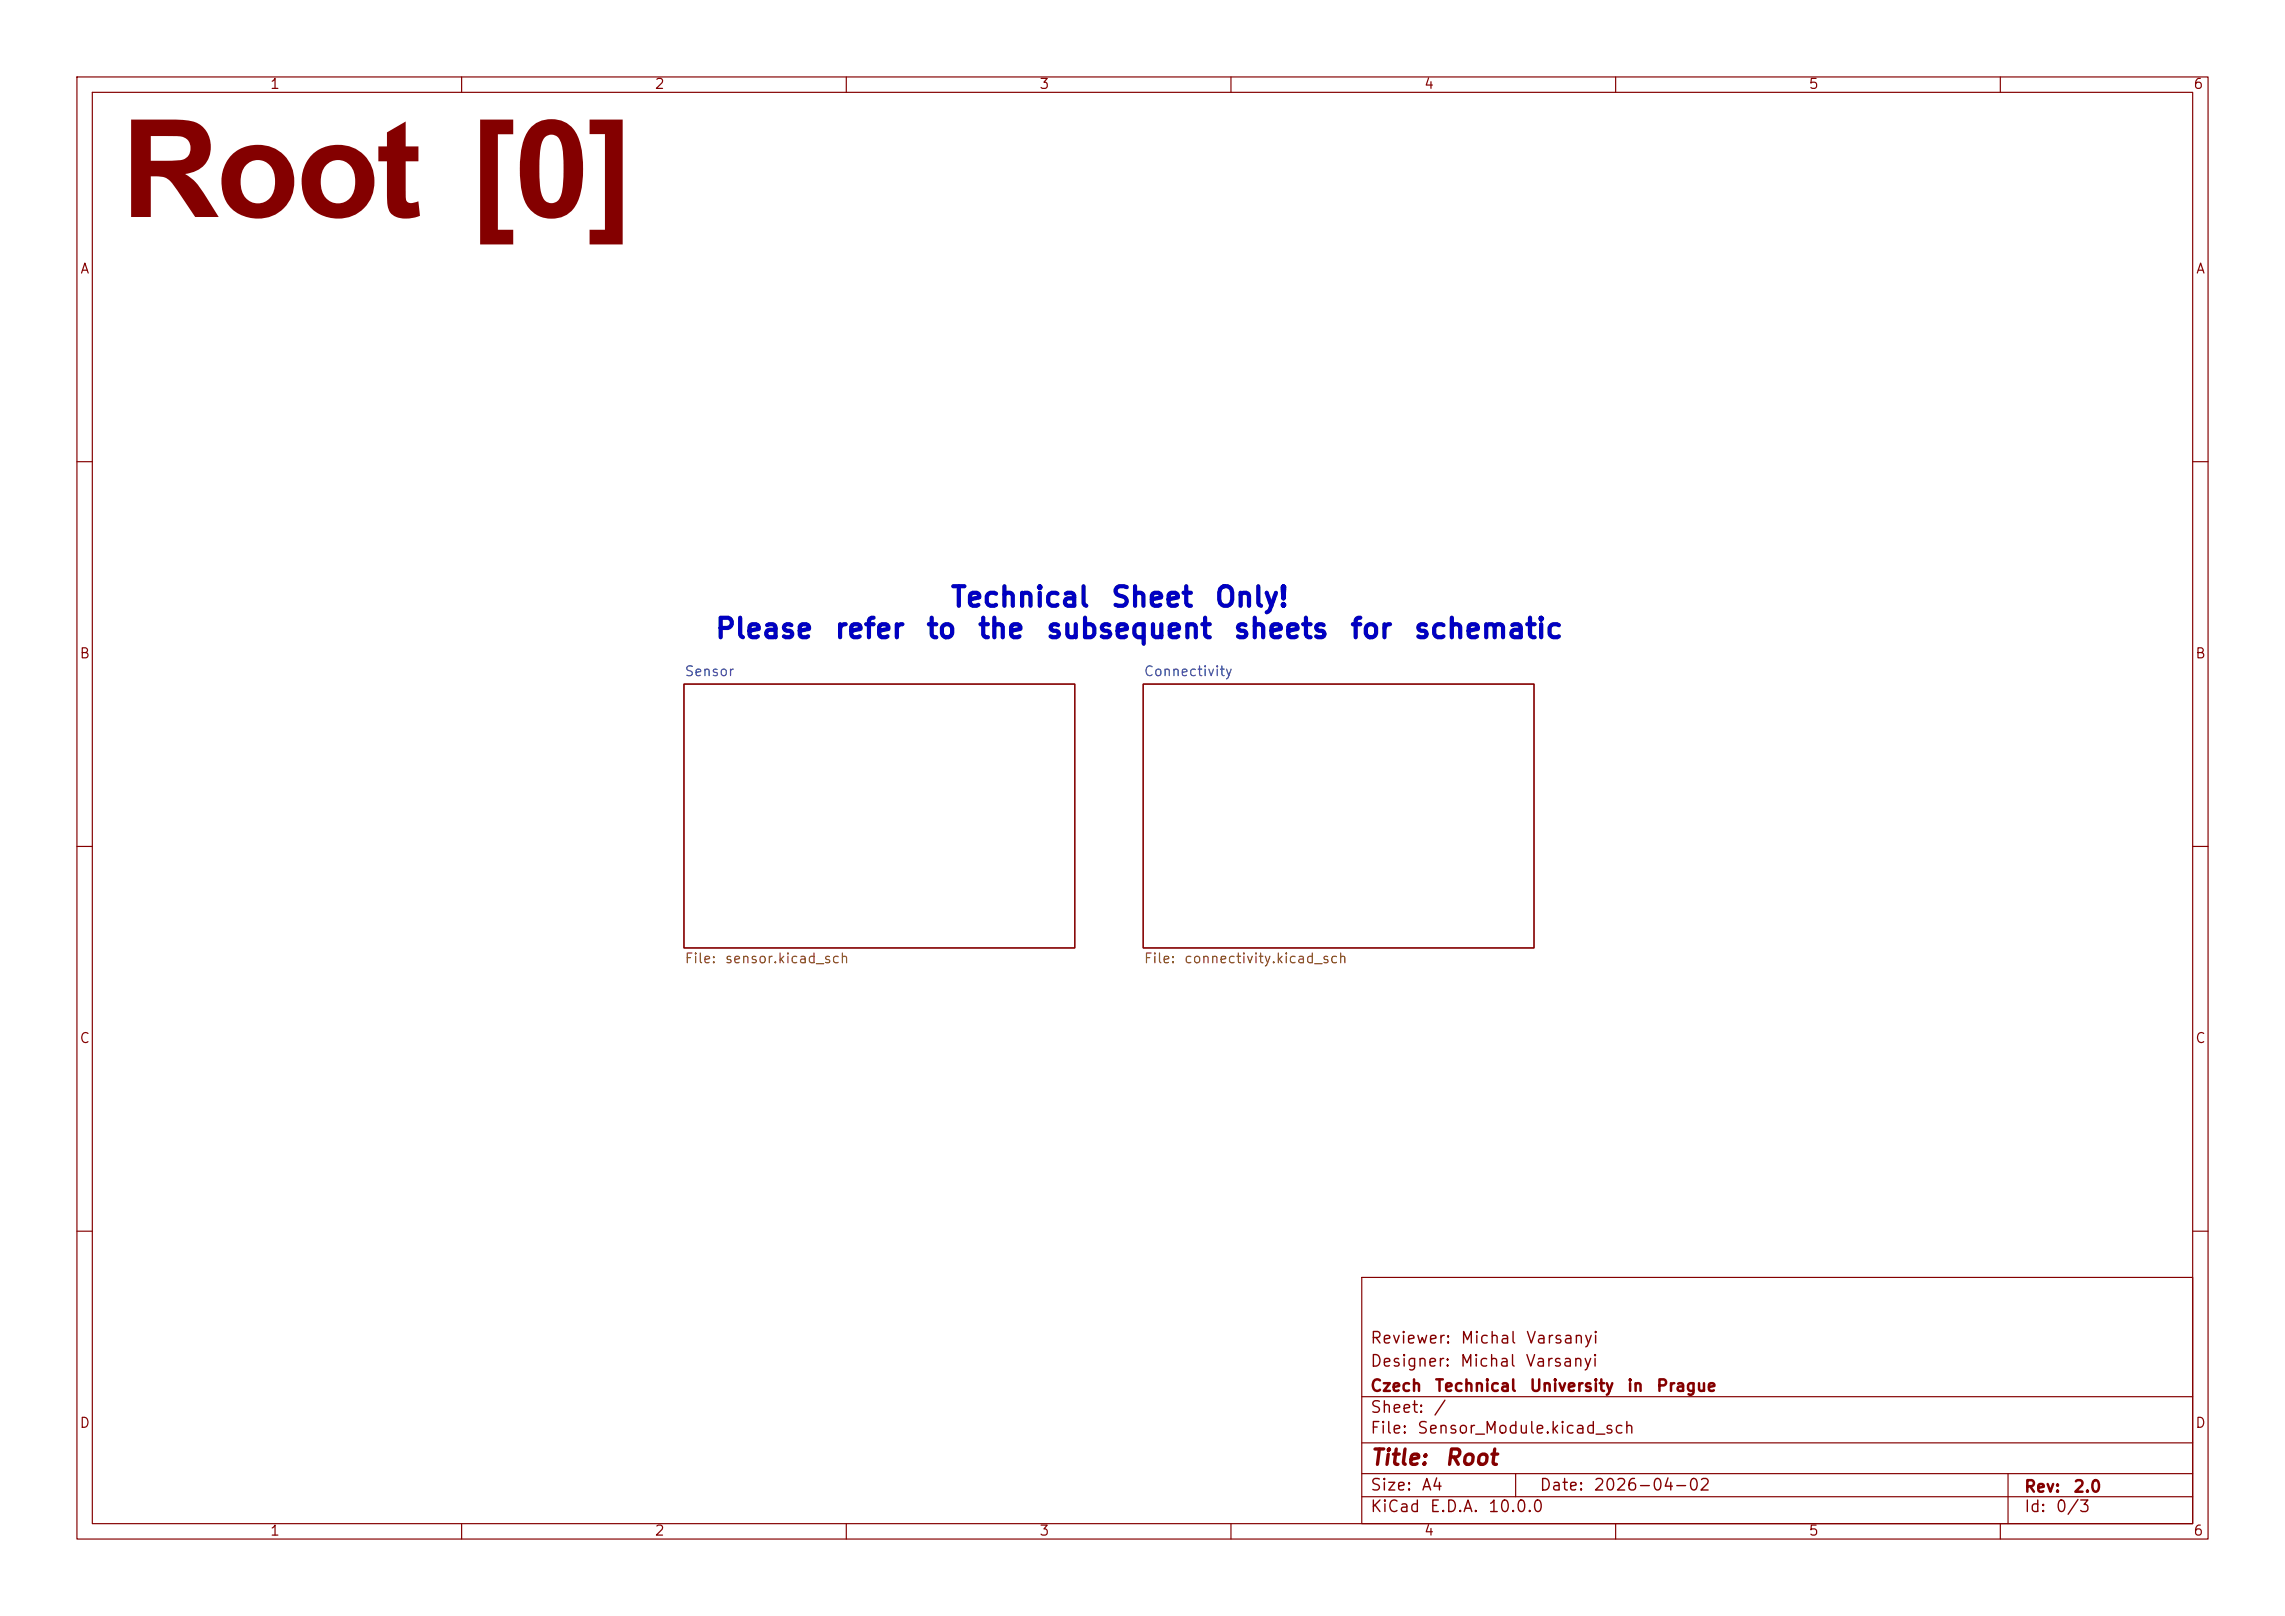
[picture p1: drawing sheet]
<svg xmlns="http://www.w3.org/2000/svg" width="297mm" height="210mm" viewBox="0 0 297 210" stroke-linecap="round" stroke-linejoin="round" font-family="sans-serif">
<defs><g id="words">
<text font-size="17.7" fill="#840000" x="15.7" y="28.2">Root [0]</text>
<g font-size="2.5" fill="#0000c2">
<text x="92.8" y="83.6">Please</text>
<text x="108.3" y="83.6">refer</text>
<text x="120.2" y="83.6">to</text>
<text x="123.4" y="79.5">Technical</text>
<text x="126.9" y="83.6">the</text>
<text x="135.8" y="83.6">subsequent</text>
<text x="144.3" y="79.5">Sheet</text>
<text x="157.7" y="79.5">Only!</text>
<text x="160.2" y="83.6">sheets</text>
<text x="175.3" y="83.6">for</text>
<text x="183.6" y="83.6">schematic</text>
</g>
<g font-size="2" fill="#840000">
<text x="178" y="190.9">Title:</text>
<text x="187.7" y="190.9">Root</text>
</g>
<g font-size="1.5" fill="#840000">
<text x="178" y="178">Designer:</text>
<text x="178" y="175">Reviewer:</text>
<text x="189.7" y="178">Michal</text>
<text x="189.7" y="175">Michal</text>
<text x="198.2" y="178">Varsanyi</text>
<text x="198.2" y="175">Varsanyi</text>
<text x="178" y="184">Sheet:</text>
<text x="178" y="181.2">Czech</text>
<text x="186.2" y="184">/</text>
<text x="186.4" y="181.2">Technical</text>
<text x="198.7" y="181.2">University</text>
<text x="211.4" y="181.2">in</text>
<text x="215.2" y="181.2">Prague</text>
<text x="178" y="186.7">File:</text>
<text x="184.1" y="186.7">Sensor_Module.kicad_sch</text>
<text x="178" y="196.9">KiCad</text>
<text x="178" y="194.1">Size:</text>
<text x="184.7" y="194.1">A4</text>
<text x="185.7" y="196.9">E.D.A.</text>
<text x="193.3" y="196.9">10.0.0</text>
<text x="200" y="194.1">Date:</text>
<text x="207" y="194.1">2026-04-02</text>
<text x="263" y="194.3">Rev:</text>
<text x="263" y="196.9">Id:</text>
<text x="267.1" y="196.9">0/3</text>
<text x="269.4" y="194.3">2.0</text>
</g>
<g font-size="1.3" fill="#840000">
<text x="35" y="11.9">1</text>
<text x="85" y="11.9">2</text>
<text x="135" y="11.9">3</text>
<text x="185" y="11.9">4</text>
<text x="235" y="11.9">5</text>
<text x="285" y="11.9">6</text>
<text x="10.3" y="35.9">A</text>
<text x="285.3" y="35.9">A</text>
<text x="10.3" y="85.9">B</text>
<text x="285.3" y="85.9">B</text>
<text x="10.3" y="135.9">C</text>
<text x="285.3" y="135.9">C</text>
<text x="10.3" y="185.9">D</text>
<text x="285.3" y="185.9">D</text>
<text x="35" y="199.9">1</text>
<text x="85" y="199.9">2</text>
<text x="135" y="199.9">3</text>
<text x="185" y="199.9">4</text>
<text x="235" y="199.9">5</text>
<text x="285" y="199.9">6</text>
</g>
<g font-size="1.3" fill="#006464">
<text x="88.9" y="88.2">Sensor</text>
<text x="148.6" y="88.2">Connectivity</text>
</g>
<g font-size="1.3" fill="#725600">
<text x="88.9" y="125.5">File:</text>
<text x="94.1" y="125.5">sensor.kicad_sch</text>
<text x="148.6" y="125.5">File:</text>
<text x="153.8" y="125.5">connectivity.kicad_sch</text>
</g>
</g></defs>
<g fill="none" stroke="#840000" stroke-width=".15">
<path d="M10 10h277v190h-277zM12 12h273v186h-273zM60 10v2M110 10v2M160 10v2M210 10v2M260 10v2M10 60h2M285 60h2M88.9 88.9h50.8v34.3h-50.8zM148.6 88.9h50.8v34.3h-50.8zM10 110h2"/>
<path d="M285 110h2M10 160h2M177 166h108v32h-108zM285 160h2M60 198v2M110 198v2M160 198v2M177 194.5h108M177 191.5h108M177 187.5h108M177 181.5h108M197 191.5v3"/>
<path d="M210 198v2M260 198v2M261 191.5v6.5"/>
</g>
<use href="#words"/>
</svg>
